VERSION 5.8 ;
BUSBITCHARS "[]" ;
DIVIDERCHAR "/" ;
UNITS
  DATABASE MICRONS 1000 ;
END UNITS
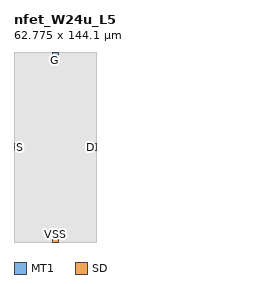
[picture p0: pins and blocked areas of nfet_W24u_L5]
MACRO nfet_W24u_L5
  CLASS BLOCK ;
  ORIGIN 0 0 ;
  FOREIGN nfet_W24u_L5 0 0 ;
  SIZE 62.775 BY 144.1 ;
  SYMMETRY X Y ;
  PIN D
    DIRECTION INOUT ;
    USE SIGNAL ;
    PORT
      LAYER MT1 ;
        RECT 60.275 69.55 62.775 74.55 ;
    END
  END D
  PIN G
    DIRECTION INPUT ;
    USE SIGNAL ;
    PORT
      LAYER MT1 ;
        RECT 28.9 141.6 33.9 144.1 ;
    END
  END G
  PIN S
    DIRECTION INOUT ;
    USE SIGNAL ;
    PORT
      LAYER MT1 ;
        RECT 0 69.55 2.5 74.55 ;
    END
  END S
  PIN VSS
    DIRECTION INOUT ;
    USE GROUND ;
    PORT
      LAYER SD ;
        RECT 28.9 0 33.9 2.5 ;
    END
  END VSS
  OBS
    LAYER SD ;
      RECT 0 0 62.775 144.1 ;
  END
END nfet_W24u_L5
END LIBRARY
